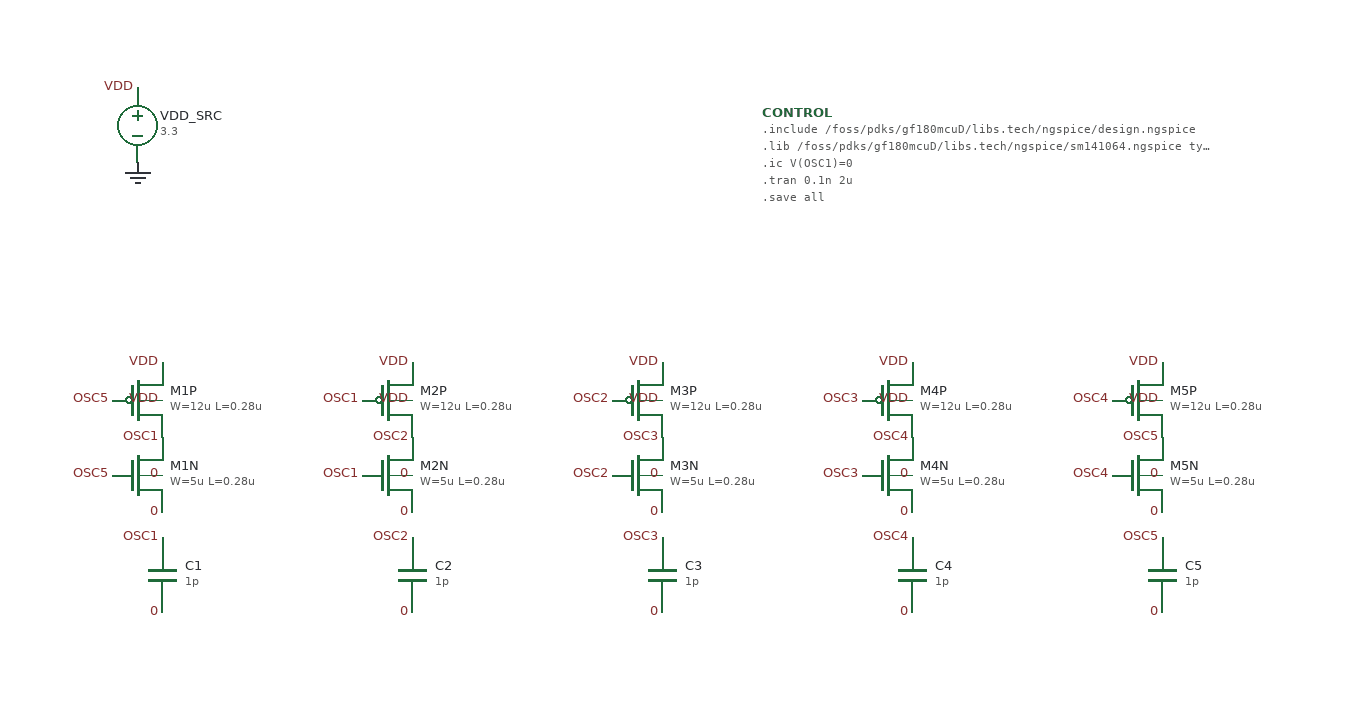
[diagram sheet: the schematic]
v {xschem version=3.4.8RC file_version=1.3}
G {}
K {}
V {}
S {}
F {}
E {}
C {devices/vsource.sym} 200 -260 0 0 {name=VDD_SRC value=3.3}
C {devices/lab_pin.sym} 200 -290 0 0 {name=p1 lab=VDD}
C {devices/gnd.sym} 200 -230 0 0 {name=l1 lab=0}
C {symbols/pfet_03v3.sym} 200 -40 0 0 {name=M1P W=12u L=0.28u nf=2 m=1}
C {symbols/nfet_03v3.sym} 200 20 0 0 {name=M1N W=5u L=0.28u nf=2 m=1}
C {devices/lab_pin.sym} 180 -40 0 0 {name=p2 lab=OSC5}
C {devices/lab_pin.sym} 180 20 0 0 {name=p3 lab=OSC5}
C {devices/lab_pin.sym} 220 -70 0 0 {name=p4 lab=VDD}
C {devices/lab_pin.sym} 220 -40 0 0 {name=p5 lab=VDD}
C {devices/lab_pin.sym} 220 -10 0 0 {name=p6 lab=OSC1}
C {devices/lab_pin.sym} 220 20 0 0 {name=p7 lab=0}
C {devices/lab_pin.sym} 220 50 0 0 {name=p8 lab=0}
C {devices/capa.sym} 220 100 0 0 {name=C1 value=1p}
C {devices/lab_pin.sym} 220 70 0 0 {name=p37 lab=OSC1}
C {devices/lab_pin.sym} 220 130 0 0 {name=p38 lab=0}
C {symbols/pfet_03v3.sym} 400 -40 0 0 {name=M2P W=12u L=0.28u nf=2 m=1}
C {symbols/nfet_03v3.sym} 400 20 0 0 {name=M2N W=5u L=0.28u nf=2 m=1}
C {devices/lab_pin.sym} 380 -40 0 0 {name=p9 lab=OSC1}
C {devices/lab_pin.sym} 380 20 0 0 {name=p10 lab=OSC1}
C {devices/lab_pin.sym} 420 -70 0 0 {name=p11 lab=VDD}
C {devices/lab_pin.sym} 420 -40 0 0 {name=p12 lab=VDD}
C {devices/lab_pin.sym} 420 -10 0 0 {name=p13 lab=OSC2}
C {devices/lab_pin.sym} 420 20 0 0 {name=p14 lab=0}
C {devices/lab_pin.sym} 420 50 0 0 {name=p15 lab=0}
C {devices/capa.sym} 420 100 0 0 {name=C2 value=1p}
C {devices/lab_pin.sym} 420 70 0 0 {name=p39 lab=OSC2}
C {devices/lab_pin.sym} 420 130 0 0 {name=p40 lab=0}
C {symbols/pfet_03v3.sym} 600 -40 0 0 {name=M3P W=12u L=0.28u nf=2 m=1}
C {symbols/nfet_03v3.sym} 600 20 0 0 {name=M3N W=5u L=0.28u nf=2 m=1}
C {devices/lab_pin.sym} 580 -40 0 0 {name=p16 lab=OSC2}
C {devices/lab_pin.sym} 580 20 0 0 {name=p17 lab=OSC2}
C {devices/lab_pin.sym} 620 -70 0 0 {name=p18 lab=VDD}
C {devices/lab_pin.sym} 620 -40 0 0 {name=p19 lab=VDD}
C {devices/lab_pin.sym} 620 -10 0 0 {name=p20 lab=OSC3}
C {devices/lab_pin.sym} 620 20 0 0 {name=p21 lab=0}
C {devices/lab_pin.sym} 620 50 0 0 {name=p22 lab=0}
C {devices/capa.sym} 620 100 0 0 {name=C3 value=1p}
C {devices/lab_pin.sym} 620 70 0 0 {name=p41 lab=OSC3}
C {devices/lab_pin.sym} 620 130 0 0 {name=p42 lab=0}
C {symbols/pfet_03v3.sym} 800 -40 0 0 {name=M4P W=12u L=0.28u nf=2 m=1}
C {symbols/nfet_03v3.sym} 800 20 0 0 {name=M4N W=5u L=0.28u nf=2 m=1}
C {devices/lab_pin.sym} 780 -40 0 0 {name=p23 lab=OSC3}
C {devices/lab_pin.sym} 780 20 0 0 {name=p24 lab=OSC3}
C {devices/lab_pin.sym} 820 -70 0 0 {name=p25 lab=VDD}
C {devices/lab_pin.sym} 820 -40 0 0 {name=p26 lab=VDD}
C {devices/lab_pin.sym} 820 -10 0 0 {name=p27 lab=OSC4}
C {devices/lab_pin.sym} 820 20 0 0 {name=p28 lab=0}
C {devices/lab_pin.sym} 820 50 0 0 {name=p29 lab=0}
C {devices/capa.sym} 820 100 0 0 {name=C4 value=1p}
C {devices/lab_pin.sym} 820 70 0 0 {name=p43 lab=OSC4}
C {devices/lab_pin.sym} 820 130 0 0 {name=p44 lab=0}
C {symbols/pfet_03v3.sym} 1000 -40 0 0 {name=M5P W=12u L=0.28u nf=2 m=1}
C {symbols/nfet_03v3.sym} 1000 20 0 0 {name=M5N W=5u L=0.28u nf=2 m=1}
C {devices/lab_pin.sym} 980 -40 0 0 {name=p30 lab=OSC4}
C {devices/lab_pin.sym} 980 20 0 0 {name=p31 lab=OSC4}
C {devices/lab_pin.sym} 1020 -70 0 0 {name=p32 lab=VDD}
C {devices/lab_pin.sym} 1020 -40 0 0 {name=p33 lab=VDD}
C {devices/lab_pin.sym} 1020 -10 0 0 {name=p34 lab=OSC5}
C {devices/lab_pin.sym} 1020 20 0 0 {name=p35 lab=0}
C {devices/lab_pin.sym} 1020 50 0 0 {name=p36 lab=0}
C {devices/capa.sym} 1020 100 0 0 {name=C5 value=1p}
C {devices/lab_pin.sym} 1020 70 0 0 {name=p45 lab=OSC5}
C {devices/lab_pin.sym} 1020 130 0 0 {name=p46 lab=0}
C {devices/code_shown.sym} 700 -270 0 0 {name=CONTROL only_toplevel=true value=".include /foss/pdks/gf180mcuD/libs.tech/ngspice/design.ngspice
.lib /foss/pdks/gf180mcuD/libs.tech/ngspice/sm141064.ngspice typical
.ic V(OSC1)=0
.tran 0.1n 2u
.save all"}
B 2 1100 -290 2060 -70 {flags=graph
rawfile=/home/irman/PandaChip/designs/lo/lo_tb_v2.raw
sim_type=tran
autoload=1
color="4 12 5"
y1=-0.333
y2=3.63
divy=4
x1=0
x2=1.46e-07
divx=8
node="osc1
osc3
osc5"
}
